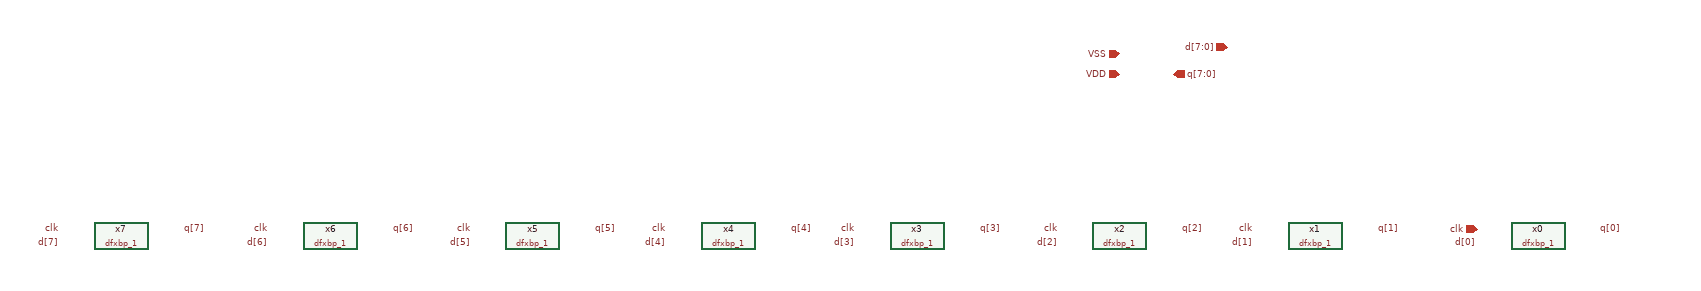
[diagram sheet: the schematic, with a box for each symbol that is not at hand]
v {xschem version=3.4.8RC file_version=1.3}
G {}
K {}
V {}
S {}
F {}
E {}
C {sky130_stdcells/dfxbp_1.sym} 450 20 0 0 {name=x0 VGND=VSS VNB=VSS VPB=VDD VPWR=VDD prefix=sky130_fd_sc_hd__ }
C {sky130_stdcells/dfxbp_1.sym} 120 20 0 0 {name=x1 VGND=VSS VNB=VSS VPB=VDD VPWR=VDD prefix=sky130_fd_sc_hd__ }
C {sky130_stdcells/dfxbp_1.sym} -170 20 0 0 {name=x2 VGND=VSS VNB=VSS VPB=VDD VPWR=VDD prefix=sky130_fd_sc_hd__ }
C {sky130_stdcells/dfxbp_1.sym} -470 20 0 0 {name=x3 VGND=VSS VNB=VSS VPB=VDD VPWR=VDD prefix=sky130_fd_sc_hd__ }
C {sky130_stdcells/dfxbp_1.sym} -750 20 0 0 {name=x4 VGND=VSS VNB=VSS VPB=VDD VPWR=VDD prefix=sky130_fd_sc_hd__ }
C {sky130_stdcells/dfxbp_1.sym} -1040 20 0 0 {name=x5 VGND=VSS VNB=VSS VPB=VDD VPWR=VDD prefix=sky130_fd_sc_hd__ }
C {sky130_stdcells/dfxbp_1.sym} -1340 20 0 0 {name=x6 VGND=VSS VNB=VSS VPB=VDD VPWR=VDD prefix=sky130_fd_sc_hd__ }
C {sky130_stdcells/dfxbp_1.sym} -1650 20 0 0 {name=x7 VGND=VSS VNB=VSS VPB=VDD VPWR=VDD prefix=sky130_fd_sc_hd__ }
C {ipin.sym} -10 -260 0 0 {name=p1 lab=d[7:0]}
C {lab_pin.sym} 30 10 1 0 {name=p3 sig_type=std_logic lab=clk}
C {lab_pin.sym} -260 10 1 0 {name=p4 sig_type=std_logic lab=clk}
C {lab_pin.sym} -560 10 1 0 {name=p5 sig_type=std_logic lab=clk}
C {lab_pin.sym} -840 10 1 0 {name=p6 sig_type=std_logic lab=clk}
C {lab_pin.sym} -1130 10 1 0 {name=p7 sig_type=std_logic lab=clk}
C {lab_pin.sym} -1430 10 1 0 {name=p8 sig_type=std_logic lab=clk}
C {lab_pin.sym} -1740 10 1 0 {name=p9 sig_type=std_logic lab=clk}
C {lab_pin.sym} 360 30 0 0 {name=p11 sig_type=std_logic lab=d[0]}
C {lab_pin.sym} 30 30 0 0 {name=p12 sig_type=std_logic lab=d[1]}
C {lab_pin.sym} -260 30 0 0 {name=p13 sig_type=std_logic lab=d[2]}
C {lab_pin.sym} -560 30 0 0 {name=p14 sig_type=std_logic lab=d[3]}
C {lab_pin.sym} -840 30 0 0 {name=p15 sig_type=std_logic lab=d[4]}
C {lab_pin.sym} -1130 30 0 0 {name=p16 sig_type=std_logic lab=d[5]}
C {lab_pin.sym} -1430 30 0 0 {name=p17 sig_type=std_logic lab=d[6]}
C {lab_pin.sym} -1740 30 0 0 {name=p18 sig_type=std_logic lab=d[7]}
C {opin.sym} -90 -220 0 0 {name=p10 lab=q[7:0]}
C {lab_pin.sym} 540 10 2 0 {name=p19 sig_type=std_logic lab=q[0]}
C {lab_pin.sym} 210 10 2 0 {name=p20 sig_type=std_logic lab=q[1]}
C {lab_pin.sym} -80 10 2 0 {name=p21 sig_type=std_logic lab=q[2]}
C {lab_pin.sym} -380 10 2 0 {name=p22 sig_type=std_logic lab=q[3]}
C {lab_pin.sym} -660 10 2 0 {name=p23 sig_type=std_logic lab=q[4]}
C {lab_pin.sym} -950 10 2 0 {name=p24 sig_type=std_logic lab=q[5]}
C {lab_pin.sym} -1250 10 2 0 {name=p25 sig_type=std_logic lab=q[6]}
C {lab_pin.sym} -1560 10 2 0 {name=p26 sig_type=std_logic lab=q[7]}
C {iopin.sym} -170 -220 0 0 {name=p27 lab=VDD}
C {iopin.sym} -170 -250 0 0 {name=p28 lab=VSS}
C {ipin.sym} 360 10 1 0 {name=p2 lab=clk}
